VERSION 5.8 ;
BUSBITCHARS "[]" ;

# Hard macros whose supply pins are stubs on their walls rather than a field
# of pins across the top.  Nothing can cross a stub like that, so the only way
# to reach one is to grow it sideways out of the macro and into the grid
# beside it.
#
# Each macro blocks metal1 through metal4 over its body and carries a stub on
# every wall it has, of both nets and in both directions: metal5 is horizontal
# so those grow east or west, metal6 is vertical so those grow north or south.
# On the three non-rectangular ones the walls of the notch -- the inside of
# the L, the stem of the T, the bend of the U -- carry stubs as well as the
# outer walls do, and a stub is on whichever wall faces the way it has to go.
#
# All four are 25.2um tall, which is 18 FreePDK45 rows, so a macro placed on a
# row boundary ends on one and the rows cut around it come out whole.
#
# As in polygon_macro.lef the non-rectangular outlines are carried by the
# OVERLAP-layer obstruction and SIZE is only its bounding box.  A notch wall
# is an edge of the macro just as much as the sides of its bounding box are:
# a stub there grows into the notch, which is ordinary core area, not through
# the body behind it.

# A plain rectangle, one stub of each net on each of its four walls.  It
# declares no OVERLAP obstruction at all, which is what every macro in a
# rectangular library looks like, so the outline falls back to the placement
# bounding box.
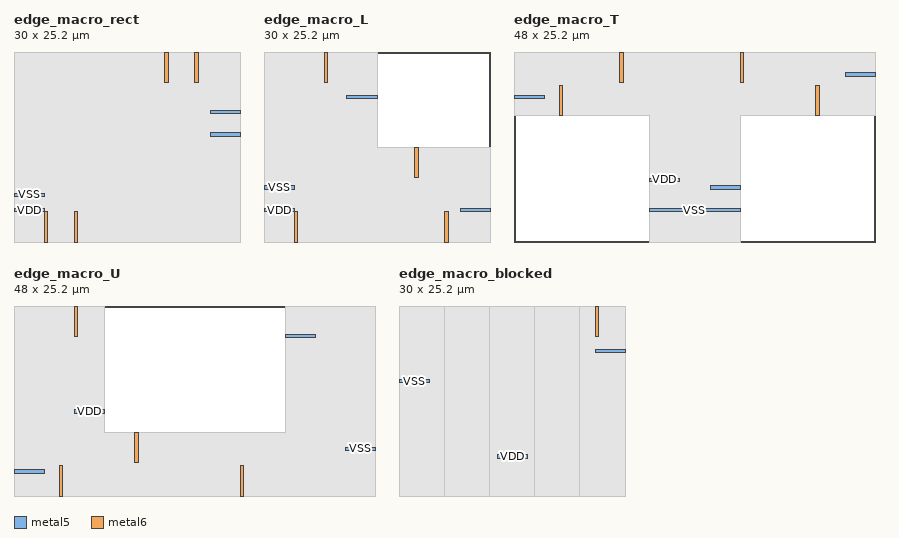
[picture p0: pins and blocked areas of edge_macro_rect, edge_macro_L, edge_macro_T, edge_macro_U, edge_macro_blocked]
MACRO edge_macro_rect
  CLASS BLOCK ;
  FOREIGN edge_macro_rect 0 0 ;
  ORIGIN 0 0 ;
  SYMMETRY X Y R90 ;
  SIZE 30.000 BY 25.200 ;
  PIN VDD
    DIRECTION INOUT ;
    USE POWER ;
    PORT
      LAYER metal5 ;
      RECT 0.000 4.000 4.000 4.480 ;
      RECT 26.000 14.000 30.000 14.480 ;
      LAYER metal6 ;
      RECT 4.000 0.000 4.480 4.000 ;
      RECT 20.000 21.200 20.480 25.200 ;
    END
  END VDD
  PIN VSS
    DIRECTION INOUT ;
    USE GROUND ;
    PORT
      LAYER metal5 ;
      RECT 0.000 6.000 4.000 6.480 ;
      RECT 26.000 17.000 30.000 17.480 ;
      LAYER metal6 ;
      RECT 8.000 0.000 8.480 4.000 ;
      RECT 24.000 21.200 24.480 25.200 ;
    END
  END VSS
  OBS
    LAYER metal1 ;
      RECT 0.000 0.000 30.000 25.200 ;
    LAYER metal2 ;
      RECT 0.000 0.000 30.000 25.200 ;
    LAYER metal3 ;
      RECT 0.000 0.000 30.000 25.200 ;
    LAYER metal4 ;
      RECT 0.000 0.000 30.000 25.200 ;
  END
END edge_macro_rect

# An L: the notch is x >= 15, y >= 12.6, so the macro has six walls.  West and
# south are outer walls, east is both the far side of the foot and the wall of
# the notch, north is both the floor of the notch and the top of the leg.
# Every one of them carries a stub.
MACRO edge_macro_L
  CLASS BLOCK ;
  FOREIGN edge_macro_L 0 0 ;
  ORIGIN 0 0 ;
  SYMMETRY X Y R90 ;
  SIZE 30.000 BY 25.200 ;
  PIN VDD
    DIRECTION INOUT ;
    USE POWER ;
    PORT
      LAYER metal5 ;
      RECT 0.000 4.000 4.000 4.480 ;
      RECT 26.000 4.000 30.000 4.480 ;
      LAYER metal6 ;
      RECT 4.000 0.000 4.480 4.000 ;
      RECT 20.000 8.600 20.480 12.600 ;
    END
  END VDD
  PIN VSS
    DIRECTION INOUT ;
    USE GROUND ;
    PORT
      LAYER metal5 ;
      RECT 0.000 7.000 4.000 7.480 ;
      RECT 11.000 19.000 15.000 19.480 ;
      LAYER metal6 ;
      RECT 24.000 0.000 24.480 4.000 ;
      RECT 8.000 21.200 8.480 25.200 ;
    END
  END VSS
  OBS
    LAYER metal1 ;
      POLYGON 0.000 0.000 30.000 0.000 30.000 12.600 15.000 12.600 15.000 25.200 0.000 25.200 ;
    LAYER metal2 ;
      POLYGON 0.000 0.000 30.000 0.000 30.000 12.600 15.000 12.600 15.000 25.200 0.000 25.200 ;
    LAYER metal3 ;
      POLYGON 0.000 0.000 30.000 0.000 30.000 12.600 15.000 12.600 15.000 25.200 0.000 25.200 ;
    LAYER metal4 ;
      POLYGON 0.000 0.000 30.000 0.000 30.000 12.600 15.000 12.600 15.000 25.200 0.000 25.200 ;
    LAYER OVERLAP ;
      POLYGON 0.000 0.000 30.000 0.000 30.000 12.600 15.000 12.600 15.000 25.200 0.000 25.200 ;
  END
END edge_macro_L

# A T standing on its stem: the bar is y >= 16.8 across the full width and the
# stem is 18 <= x <= 30.  West and east are both the walls of the stem, which
# face into the notch either side of it, and the ends of the bar; south is
# both the foot of the stem and the underside of the bar; north is the top of
# the bar.
#
# The VSS stub at y = 4 is laid all the way across the stem, so it reaches the
# outline at both ends and neither is more the way out than the other.  That
# is the one stub here whose direction the outline does not settle.
MACRO edge_macro_T
  CLASS BLOCK ;
  FOREIGN edge_macro_T 0 0 ;
  ORIGIN 0 0 ;
  SYMMETRY X Y R90 ;
  SIZE 48.000 BY 25.200 ;
  PIN VDD
    DIRECTION INOUT ;
    USE POWER ;
    PORT
      LAYER metal5 ;
      RECT 18.000 8.000 22.000 8.480 ;
      RECT 44.000 22.000 48.000 22.480 ;
      LAYER metal6 ;
      RECT 6.000 16.800 6.480 20.800 ;
      RECT 14.000 21.200 14.480 25.200 ;
    END
  END VDD
  PIN VSS
    DIRECTION INOUT ;
    USE GROUND ;
    PORT
      LAYER metal5 ;
      RECT 0.000 19.000 4.000 19.480 ;
      RECT 26.000 7.000 30.000 7.480 ;
      RECT 18.000 4.000 30.000 4.480 ;
      LAYER metal6 ;
      RECT 40.000 16.800 40.480 20.800 ;
      RECT 30.000 21.200 30.480 25.200 ;
    END
  END VSS
  OBS
    LAYER metal1 ;
      POLYGON 18.000 0.000 30.000 0.000 30.000 16.800 48.000 16.800 48.000 25.200 0.000 25.200 0.000 16.800 18.000 16.800 ;
    LAYER metal2 ;
      POLYGON 18.000 0.000 30.000 0.000 30.000 16.800 48.000 16.800 48.000 25.200 0.000 25.200 0.000 16.800 18.000 16.800 ;
    LAYER metal3 ;
      POLYGON 18.000 0.000 30.000 0.000 30.000 16.800 48.000 16.800 48.000 25.200 0.000 25.200 0.000 16.800 18.000 16.800 ;
    LAYER metal4 ;
      POLYGON 18.000 0.000 30.000 0.000 30.000 16.800 48.000 16.800 48.000 25.200 0.000 25.200 0.000 16.800 18.000 16.800 ;
    LAYER OVERLAP ;
      POLYGON 18.000 0.000 30.000 0.000 30.000 16.800 48.000 16.800 48.000 25.200 0.000 25.200 0.000 16.800 18.000 16.800 ;
  END
END edge_macro_T

# A U standing on its base: the base is y <= 8.4 and the legs are x <= 12 and
# x >= 36.  West is the outer wall of the base and the inner wall of the right
# leg, east is the outer wall of the base and the inner wall of the left leg,
# south is the foot of the base and north is both the floor of the bend and
# the top of a leg.
MACRO edge_macro_U
  CLASS BLOCK ;
  FOREIGN edge_macro_U 0 0 ;
  ORIGIN 0 0 ;
  SYMMETRY X Y R90 ;
  SIZE 48.000 BY 25.200 ;
  PIN VDD
    DIRECTION INOUT ;
    USE POWER ;
    PORT
      LAYER metal5 ;
      RECT 0.000 3.000 4.000 3.480 ;
      RECT 8.000 11.000 12.000 11.480 ;
      LAYER metal6 ;
      RECT 6.000 0.000 6.480 4.000 ;
      RECT 16.000 4.400 16.480 8.400 ;
    END
  END VDD
  PIN VSS
    DIRECTION INOUT ;
    USE GROUND ;
    PORT
      LAYER metal5 ;
      RECT 44.000 6.000 48.000 6.480 ;
      RECT 36.000 21.000 40.000 21.480 ;
      LAYER metal6 ;
      RECT 30.000 0.000 30.480 4.000 ;
      RECT 8.000 21.200 8.480 25.200 ;
    END
  END VSS
  OBS
    LAYER metal1 ;
      POLYGON 0.000 0.000 48.000 0.000 48.000 25.200 36.000 25.200 36.000 8.400 12.000 8.400 12.000 25.200 0.000 25.200 ;
    LAYER metal2 ;
      POLYGON 0.000 0.000 48.000 0.000 48.000 25.200 36.000 25.200 36.000 8.400 12.000 8.400 12.000 25.200 0.000 25.200 ;
    LAYER metal3 ;
      POLYGON 0.000 0.000 48.000 0.000 48.000 25.200 36.000 25.200 36.000 8.400 12.000 8.400 12.000 25.200 0.000 25.200 ;
    LAYER metal4 ;
      POLYGON 0.000 0.000 48.000 0.000 48.000 25.200 36.000 25.200 36.000 8.400 12.000 8.400 12.000 25.200 0.000 25.200 ;
    LAYER OVERLAP ;
      POLYGON 0.000 0.000 48.000 0.000 48.000 25.200 36.000 25.200 36.000 8.400 12.000 8.400 12.000 25.200 0.000 25.200 ;
  END
END edge_macro_U

# A macro that walls its own pins in.  The two metal5 rectangles at
# 6 <= x <= 12 and 18 <= x <= 24 are the macro's own routing, not a pin of
# anything, so a strap grown out of the stub between them is cut short of the
# first one it reaches and connects nothing: VDD has no way out.  The VSS stub
# west of both reaches the grid; the one east of both would, but the test puts
# an obstruction outside the macro in its way.  The metal6 pin is on a layer
# no connect rule in that grid names, so nothing is attempted for it.
MACRO edge_macro_blocked
  CLASS BLOCK ;
  FOREIGN edge_macro_blocked 0 0 ;
  ORIGIN 0 0 ;
  SYMMETRY X Y R90 ;
  SIZE 30.000 BY 25.200 ;
  PIN VDD
    DIRECTION INOUT ;
    USE POWER ;
    PORT
      LAYER metal5 ;
      RECT 13.000 5.000 17.000 5.480 ;
      LAYER metal6 ;
      RECT 26.000 21.200 26.480 25.200 ;
    END
  END VDD
  PIN VSS
    DIRECTION INOUT ;
    USE GROUND ;
    PORT
      LAYER metal5 ;
      RECT 0.000 15.000 4.000 15.480 ;
      RECT 26.000 19.000 30.000 19.480 ;
    END
  END VSS
  OBS
    LAYER metal1 ;
      RECT 0.000 0.000 30.000 25.200 ;
    LAYER metal2 ;
      RECT 0.000 0.000 30.000 25.200 ;
    LAYER metal3 ;
      RECT 0.000 0.000 30.000 25.200 ;
    LAYER metal4 ;
      RECT 0.000 0.000 30.000 25.200 ;
    LAYER metal5 ;
      RECT 6.000 0.000 12.000 25.200 ;
      RECT 18.000 0.000 24.000 25.200 ;
  END
END edge_macro_blocked

END LIBRARY
